VERSION 5.7 ;
BUSBITCHARS "[]" ;
DIVIDERCHAR "/" ;

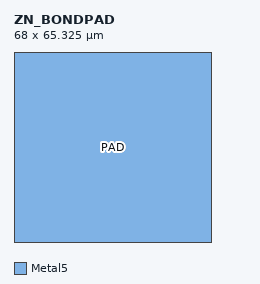
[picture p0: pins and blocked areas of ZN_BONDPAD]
MACRO ZN_BONDPAD
  CLASS BLOCK ;
  ORIGIN 0 0 ;
  SIZE 68.000 BY 65.325 ;
  SYMMETRY X Y ;
  PIN PAD
    DIRECTION INOUT ;
    USE SIGNAL ;
    PORT
      LAYER Metal5 ;
        RECT 0.000 0.000 68.000 65.325 ;
    END
  END PAD
  OBS
    LAYER Metal2 ;
      RECT 0.000 0.000 68.000 65.325 ;
    LAYER Metal3 ;
      RECT 0.000 0.000 68.000 65.325 ;
    LAYER Metal4 ;
      RECT 0.000 0.000 68.000 65.325 ;
  END
END ZN_BONDPAD

END LIBRARY
